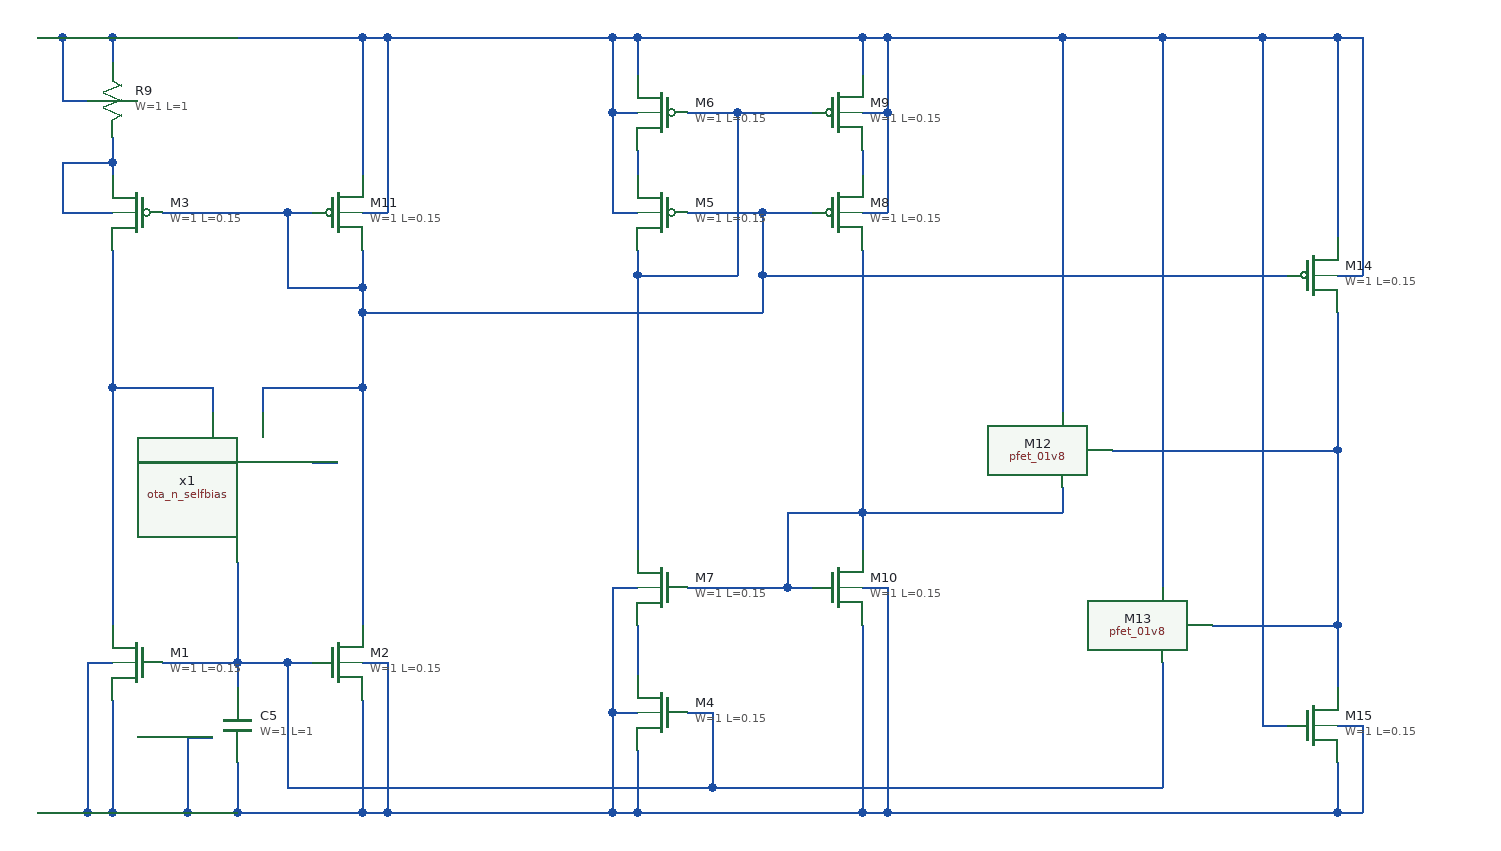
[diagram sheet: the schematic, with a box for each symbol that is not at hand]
v {xschem version=3.4.6 file_version=1.2}
G {}
K {}
V {}
S {}
E {}
N 0 -200 0 -190 {lab=#net1}
N -40 -160 0 -160 {lab=#net1}
N -40 -250 -20 -250 {lab=#net2}
N -40 -300 -40 -250 {lab=#net2}
N -40 -300 0 -300 {lab=#net2}
N 0 -300 0 -280 {lab=#net2}
N 0 -300 200 -300 {lab=#net2}
N 200 -300 200 -190 {lab=#net2}
N 200 -160 220 -160 {lab=#net2}
N 220 -300 220 -160 {lab=#net2}
N 200 -300 220 -300 {lab=#net2}
N -40 -200 0 -200 {lab=#net1}
N -40 -200 -40 -160 {lab=#net1}
N -20 200 0 200 {lab=#net3}
N -20 320 0 320 {lab=#net3}
N 140 -160 160 -160 {lab=#net4}
N 140 -160 140 -100 {lab=#net4}
N 140 -100 200 -100 {lab=#net4}
N 200 -130 200 -100 {lab=#net4}
N 0 -220 0 -200 {lab=#net1}
N 40 -160 140 -160 {lab=#net4}
N 0 -20 0 170 {lab=#net5}
N 200 -20 200 170 {lab=#net4}
N 140 200 160 200 {lab=#net6}
N 100 120 100 200 {lab=#net6}
N 80 -20 80 -0 {lab=#net5}
N 0 -20 80 -20 {lab=#net5}
N 120 -20 120 -0 {lab=#net4}
N 120 -20 200 -20 {lab=#net4}
N 200 230 200 320 {lab=#net3}
N 200 200 220 200 {lab=#net3}
N 220 200 220 320 {lab=#net3}
N 200 320 220 320 {lab=#net3}
N 100 280 100 320 {lab=#net3}
N 100 200 100 220 {lab=#net6}
N 60 260 80 260 {lab=#net3}
N 60 260 60 320 {lab=#net3}
N 40 200 100 200 {lab=#net6}
N 0 -130 0 -20 {lab=#net5}
N 200 -80 200 -20 {lab=#net4}
N 60 320 100 320 {lab=#net3}
N -0 320 60 320 {lab=#net3}
N -20 200 -20 320 {lab=#net3}
N 0 230 0 320 {lab=#net3}
N 160 40 180 40 {lab=#net7}
N 20 40 40 40 {lab=#net8}
N -60 -300 -40 -300 {lab=#net2}
N -60 320 -20 320 {lab=#net3}
N 400 -300 420 -300 {lab=#net2}
N 420 -300 420 -270 {lab=#net2}
N 420 -210 420 -190 {lab=#net9}
N 400 -160 420 -160 {lab=#net2}
N 400 -240 400 -160 {lab=#net2}
N 400 -240 420 -240 {lab=#net2}
N 400 -300 400 -240 {lab=#net2}
N 420 -110 420 110 {lab=#net10}
N 420 -110 500 -110 {lab=#net10}
N 460 -240 500 -240 {lab=#net10}
N 520 -160 560 -160 {lab=#net4}
N 220 -300 400 -300 {lab=#net2}
N 460 -160 520 -160 {lab=#net4}
N 200 -100 200 -80 {lab=#net4}
N 500 -240 560 -240 {lab=#net10}
N 500 -240 500 -110 {lab=#net10}
N 520 -110 520 -80 {lab=#net4}
N 200 -80 520 -80 {lab=#net4}
N 420 -130 420 -110 {lab=#net10}
N 400 140 420 140 {lab=#net3}
N 400 140 400 240 {lab=#net3}
N 400 240 420 240 {lab=#net3}
N 220 320 400 320 {lab=#net3}
N 100 320 200 320 {lab=#net3}
N 400 240 400 320 {lab=#net3}
N 420 270 420 320 {lab=#net3}
N 420 170 420 210 {lab=#net11}
N 140 200 140 300 {lab=#net6}
N 140 300 480 300 {lab=#net6}
N 480 240 480 300 {lab=#net6}
N 460 240 480 240 {lab=#net6}
N 540 140 560 140 {lab=#net12}
N 100 200 140 200 {lab=#net6}
N 600 80 600 110 {lab=#net12}
N 600 170 600 320 {lab=#net3}
N 600 140 620 140 {lab=#net3}
N 620 140 620 320 {lab=#net3}
N 600 320 620 320 {lab=#net3}
N 540 80 540 140 {lab=#net12}
N 600 -210 600 -190 {lab=#net13}
N 420 -300 600 -300 {lab=#net2}
N 600 -300 600 -270 {lab=#net2}
N 600 -300 620 -300 {lab=#net2}
N 620 -300 620 -240 {lab=#net2}
N 600 -240 620 -240 {lab=#net2}
N 600 -160 620 -160 {lab=#net2}
N 620 -240 620 -160 {lab=#net2}
N 980 -300 980 -140 {lab=#net2}
N 980 -110 1000 -110 {lab=#net2}
N 1000 -300 1000 -110 {lab=#net2}
N 980 -300 1000 -300 {lab=#net2}
N 600 80 760 80 {lab=#net12}
N 760 60 760 80 {lab=#net12}
N 460 140 540 140 {lab=#net12}
N 600 -130 600 80 {lab=#net12}
N 520 -110 940 -110 {lab=#net4}
N 920 -300 980 -300 {lab=#net2}
N 520 -160 520 -110 {lab=#net4}
N 400 320 420 320 {lab=#net3}
N 420 320 600 320 {lab=#net3}
N 840 200 840 300 {lab=#net6}
N 800 30 980 30 {lab=#net14}
N 980 -80 980 30 {lab=#net14}
N 620 320 980 320 {lab=#net3}
N 980 280 980 320 {lab=#net3}
N 980 250 1000 250 {lab=#net3}
N 1000 250 1000 320 {lab=#net3}
N 980 320 1000 320 {lab=#net3}
N 980 170 980 220 {lab=#net14}
N 920 250 940 250 {lab=#net2}
N 920 -300 920 250 {lab=#net2}
N 760 -300 760 0 {lab=#net2}
N 880 170 980 170 {lab=#net14}
N 840 -300 840 140 {lab=#net2}
N 840 -300 920 -300 {lab=#net2}
N 620 -300 760 -300 {lab=#net2}
N 760 -300 840 -300 {lab=#net2}
N 540 80 600 80 {lab=#net12}
N 480 300 840 300 {lab=#net6}
N 980 30 980 170 {lab=#net14}
C {ota_n_selfbias.sym} 100 80 3 1 {name=x1}
C {sky130_fd_pr/nfet_01v8.sym} 180 200 0 0 {name=M2
L=0.15
W=1  
nf=1 mult=1
model=nfet_01v8
spiceprefix=X
}
C {sky130_fd_pr/nfet_01v8.sym} 20 200 0 1 {name=M1
L=0.15
W=1  
nf=1 mult=1
model=nfet_01v8
spiceprefix=X
}
C {sky130_fd_pr/pfet_01v8.sym} 180 -160 0 0 {name=M11
L=0.15
W=1
nf=1 mult=1
model=pfet_01v8
spiceprefix=X
}
C {sky130_fd_pr/pfet_01v8.sym} 20 -160 0 1 {name=M3
L=0.15
W=1
nf=1 mult=1
model=pfet_01v8
spiceprefix=X
}
C {sky130_fd_pr/res_xhigh_po.sym} 0 -250 0 0 {name=R9
W=1
L=1
model=res_xhigh_po
spiceprefix=X
 mult=1}
C {sky130_fd_pr/vpp_cap.sym} 100 250 0 0 {name=C5
model=cap_vpp_11p5x11p7_l1m1m2m3m4_shieldm5
W=1
L=1 
mult=1 
spiceprefix=X}
C {sky130_fd_pr/nfet_01v8.sym} 440 240 0 1 {name=M4
L=0.15
W=1  
nf=1 mult=1
model=nfet_01v8
spiceprefix=X
}
C {sky130_fd_pr/pfet_01v8.sym} 440 -160 0 1 {name=M5
L=0.15
W=1
nf=1 mult=1
model=pfet_01v8
spiceprefix=X
}
C {sky130_fd_pr/pfet_01v8.sym} 440 -240 0 1 {name=M6
L=0.15
W=1
nf=1 mult=1
model=pfet_01v8
spiceprefix=X
}
C {sky130_fd_pr/nfet_01v8.sym} 440 140 0 1 {name=M7
L=0.15
W=1  
nf=1 mult=1
model=nfet_01v8
spiceprefix=X
}
C {sky130_fd_pr/pfet_01v8.sym} 580 -160 0 0 {name=M8
L=0.15
W=1
nf=1 mult=1
model=pfet_01v8
spiceprefix=X
}
C {sky130_fd_pr/pfet_01v8.sym} 580 -240 0 0 {name=M9
L=0.15
W=1
nf=1 mult=1
model=pfet_01v8
spiceprefix=X
}
C {sky130_fd_pr/nfet_01v8.sym} 580 140 0 0 {name=M10
L=0.15
W=1  
nf=1 mult=1
model=nfet_01v8
spiceprefix=X
}
C {sky130_fd_pr/pfet_01v8.sym} 779.78515625 30.478515625 0 1 {name=M12
L=0.15
W=1
nf=1 mult=1
model=pfet_01v8
spiceprefix=X
}
C {sky130_fd_pr/pfet_01v8.sym} 960 -110 0 0 {name=M14
L=0.15
W=1
nf=1 mult=1
model=pfet_01v8
spiceprefix=X
}
C {sky130_fd_pr/pfet_01v8.sym} 859.78515625 170.478515625 0 1 {name=M13
L=0.15
W=1
nf=1 mult=1
model=pfet_01v8
spiceprefix=X
}
C {sky130_fd_pr/nfet_01v8.sym} 960 250 0 0 {name=M15
L=0.15
W=1  
nf=1 mult=1
model=nfet_01v8
spiceprefix=X
}
